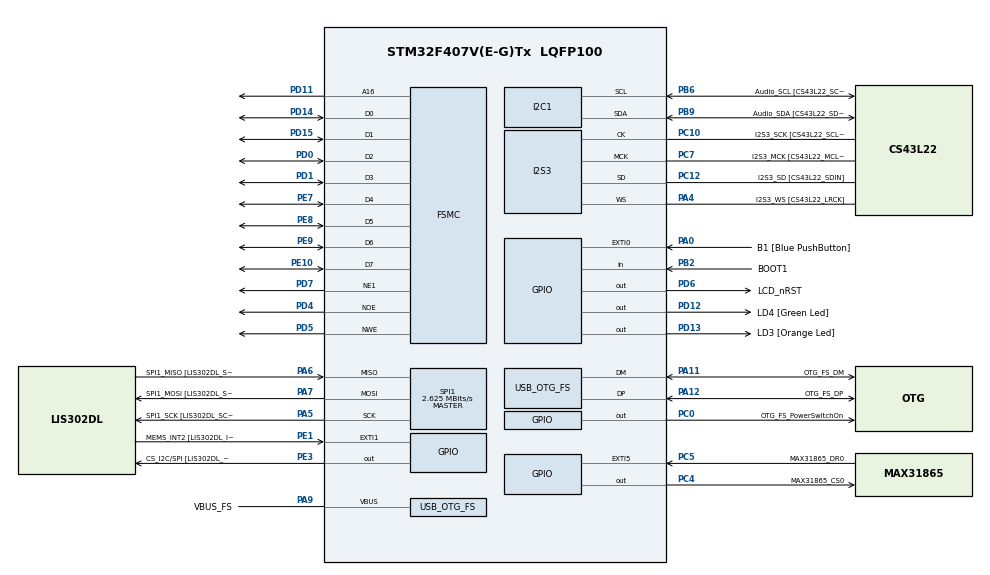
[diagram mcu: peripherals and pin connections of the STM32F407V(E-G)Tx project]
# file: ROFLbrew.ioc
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FSMC.BusTurnAroundDuration1=0
FSMC.DataSetupTime1=13
I2S3.AudioFreq=I2S_AUDIOFREQ_96K
I2S3.AudioFreq-Half_Duplex_Master=I2S_AUDIOFREQ_96K
I2S3.ErrorAudioFreq=-2.34 %
I2S3.ErrorAudioFreq-Half_Duplex_Master=0.8 %
I2S3.RealAudioFreq=93.75 KHz
I2S3.RealAudioFreq-Half_Duplex_Master=96.774 KHz
Mcu.Family=STM32F4
Mcu.Name=STM32F407V(E-G)Tx
Mcu.Package=LQFP100
NVIC.EXTI9_5_IRQn=true\:0\:0\:false\:false\:true
NVIC.OTG_FS_IRQn=true\:0\:0\:false\:false\:true
NVIC.PriorityGroup=NVIC_PRIORITYGROUP_0
NVIC.TIM8_TRG_COM_TIM14_IRQn=true\:0\:0\:false\:false\:true
PA0-WKUP.GPIO_Label=B1 [Blue PushButton]
PA0-WKUP.GPIO_ModeDefaultEXTI=GPIO_MODE_EVT_RISING
PA0-WKUP.GPIO_PuPd=GPIO_NOPULL
PA0-WKUP.Signal=GPXTI0
PA10.GPIO_Label=OTG_FS_ID
PA10.GPIO_Mode=GPIO_MODE_AF_PP
PA10.GPIO_PuPd=GPIO_NOPULL
PA10.GPIO_Speed=GPIO_SPEED_FREQ_LOW
PA10.Signal=USB_OTG_FS_ID
PA11.GPIO_Label=OTG_FS_DM
PA11.GPIO_Mode=GPIO_MODE_AF_PP
PA11.GPIO_PuPd=GPIO_NOPULL
PA11.GPIO_Speed=GPIO_SPEED_FREQ_LOW
PA11.Mode=Host_Only
PA11.Signal=USB_OTG_FS_DM
PA12.GPIO_Label=OTG_FS_DP
PA12.GPIO_Mode=GPIO_MODE_AF_PP
PA12.GPIO_PuPd=GPIO_NOPULL
PA12.GPIO_Speed=GPIO_SPEED_FREQ_LOW
PA12.Mode=Host_Only
PA12.Signal=USB_OTG_FS_DP
PA13.GPIO_Label=SWDIO
PA13.Mode=Serial_Wire
PA13.Signal=SYS_JTMS-SWDIO
PA14.GPIO_Label=SWCLK
PA14.Mode=Serial_Wire
PA14.Signal=SYS_JTCK-SWCLK
PA4.GPIO_Label=I2S3_WS [CS43L22_LRCK]
PA4.GPIO_Mode=GPIO_MODE_AF_PP
PA4.GPIO_PuPd=GPIO_NOPULL
PA4.GPIO_Speed=GPIO_SPEED_FREQ_LOW
PA4.Mode=Half_Duplex_Master
PA4.Signal=I2S3_WS
PA5.GPIO_Label=SPI1_SCK [LIS302DL_SCL/SPC]
PA5.GPIO_Mode=GPIO_MODE_AF_PP
PA5.GPIO_PuPd=GPIO_NOPULL
PA5.GPIO_Speed=GPIO_SPEED_FREQ_LOW
PA5.Mode=Full_Duplex_Master
PA5.Signal=SPI1_SCK
PA6.GPIO_Label=SPI1_MISO [LIS302DL_SDO]
PA6.GPIO_Mode=GPIO_MODE_AF_PP
PA6.GPIO_PuPd=GPIO_NOPULL
PA6.GPIO_Speed=GPIO_SPEED_FREQ_LOW
PA6.Mode=Full_Duplex_Master
PA6.Signal=SPI1_MISO
PA7.GPIO_Label=SPI1_MOSI [LIS302DL_SDA/SDI/SDO]
PA7.GPIO_Mode=GPIO_MODE_AF_PP
PA7.GPIO_PuPd=GPIO_NOPULL
PA7.GPIO_Speed=GPIO_SPEED_FREQ_LOW
PA7.Mode=Full_Duplex_Master
PA7.Signal=SPI1_MOSI
PA9.GPIO_Label=VBUS_FS
PA9.GPIO_Mode=GPIO_MODE_INPUT
PA9.GPIO_PuPd=GPIO_NOPULL
PA9.Mode=Activate_VBUS
PA9.Signal=USB_OTG_FS_VBUS
PB10.GPIO_Label=CLK_IN [MP45DT02_CLK]
PB10.GPIO_Mode=GPIO_MODE_AF_PP
PB10.GPIO_PuPd=GPIO_NOPULL
PB10.GPIO_Speed=GPIO_SPEED_FREQ_LOW
PB10.Signal=I2S2_CK
PB2.GPIO_Label=BOOT1
PB2.GPIO_Mode=GPIO_MODE_INPUT
PB2.GPIO_PuPd=GPIO_NOPULL
PB2.Signal=GPIO_Input
PB3.GPIO_Label=SWO
PB3.Signal=SYS_JTDO-SWO
PB6.GPIO_Label=Audio_SCL [CS43L22_SCL]
PB6.GPIO_Mode=GPIO_MODE_AF_OD
PB6.GPIO_PuPd=GPIO_NOPULL
PB6.GPIO_Speed=GPIO_SPEED_FREQ_LOW
PB6.Mode=I2C
PB6.Signal=I2C1_SCL
PB9.GPIO_Label=Audio_SDA [CS43L22_SDA]
PB9.GPIO_Mode=GPIO_MODE_AF_OD
PB9.GPIO_PuPd=GPIO_NOPULL
PB9.GPIO_Speed=GPIO_SPEED_FREQ_LOW
PB9.Mode=I2C
PB9.Signal=I2C1_SDA
PC0.GPIO_Label=OTG_FS_PowerSwitchOn
PC0.GPIO_PuPd=GPIO_NOPULL
PC0.GPIO_Speed=GPIO_SPEED_FREQ_LOW
PC0.PinState=GPIO_PIN_SET
PC0.Signal=GPIO_Output
PC10.GPIO_Label=I2S3_SCK [CS43L22_SCLK]
PC10.GPIO_Mode=GPIO_MODE_AF_PP
PC10.GPIO_PuPd=GPIO_NOPULL
PC10.GPIO_Speed=GPIO_SPEED_FREQ_LOW
PC10.Mode=Half_Duplex_Master
PC10.Signal=I2S3_CK
PC12.GPIO_Label=I2S3_SD [CS43L22_SDIN]
PC12.GPIO_Mode=GPIO_MODE_AF_PP
PC12.GPIO_PuPd=GPIO_NOPULL
PC12.GPIO_Speed=GPIO_SPEED_FREQ_LOW
PC12.Mode=Half_Duplex_Master
PC12.Signal=I2S3_SD
PC14-OSC32_IN.GPIO_Label=PC14-OSC32_IN
PC14-OSC32_IN.Mode=LSE-External-Oscillator
PC14-OSC32_IN.Signal=RCC_OSC32_IN
PC15-OSC32_OUT.GPIO_Label=PC15-OSC32_OUT
PC15-OSC32_OUT.Mode=LSE-External-Oscillator
PC15-OSC32_OUT.Signal=RCC_OSC32_OUT
PC3.GPIO_Label=PDM_OUT [MP45DT02_DOUT]
PC3.GPIO_Mode=GPIO_MODE_AF_PP
PC3.GPIO_PuPd=GPIO_NOPULL
PC3.GPIO_Speed=GPIO_SPEED_FREQ_LOW
PC3.Signal=I2S2_SD
PC4.GPIO_Label=MAX31865_CS0
PC4.GPIO_Speed=GPIO_SPEED_FREQ_MEDIUM
PC4.PinState=GPIO_PIN_SET
PC4.Signal=GPIO_Output
PC5.GPIO_Label=MAX31865_DR0
PC5.GPIO_ModeDefaultEXTI=GPIO_MODE_IT_FALLING
PC5.GPIO_PuPd=GPIO_PULLUP
PC5.Signal=GPXTI5
PC7.GPIO_Label=I2S3_MCK [CS43L22_MCLK]
PC7.GPIO_Mode=GPIO_MODE_AF_PP
PC7.GPIO_PuPd=GPIO_NOPULL
PC7.GPIO_Speed=GPIO_SPEED_FREQ_LOW
PC7.Mode=Master_Clock_Activated
PC7.Signal=I2S3_MCK
PD0.Mode=8b-d1
PD0.Signal=FSMC_D2
PD1.Mode=8b-d1
PD1.Signal=FSMC_D3
PD11.Mode=A16_1
PD11.Signal=FSMC_A16
PD12.GPIO_Label=LD4 [Green Led]
PD12.GPIO_PuPd=GPIO_NOPULL
PD12.GPIO_Speed=GPIO_SPEED_FREQ_LOW
PD12.Signal=GPIO_Output
PD13.GPIO_Label=LD3 [Orange Led]
PD13.GPIO_PuPd=GPIO_NOPULL
PD13.GPIO_Speed=GPIO_SPEED_FREQ_LOW
PD13.Signal=GPIO_Output
PD14.Mode=8b-d1
PD14.Signal=FSMC_D0
PD15.Mode=8b-d1
PD15.Signal=FSMC_D1
PD4.Mode=Lcd1
PD4.Signal=FSMC_NOE
PD5.Mode=Lcd1
PD5.Signal=FSMC_NWE
PD6.GPIO_Label=LCD_nRST
PD6.GPIO_ModeDefaultOutputPP=GPIO_MODE_OUTPUT_OD
PD6.GPIO_PuPd=GPIO_PULLUP
PD6.PinState=GPIO_PIN_SET
PD6.Signal=GPIO_Output
PD7.Mode=NorPsramChipSelect1_1
PD7.Signal=FSMC_NE1
PE1.GPIO_Label=MEMS_INT2 [LIS302DL_INT2]
PE1.GPIO_ModeDefaultEXTI=GPIO_MODE_EVT_RISING
PE1.GPIO_PuPd=GPIO_NOPULL
PE1.Signal=GPXTI1
PE10.Mode=8b-d1
PE10.Signal=FSMC_D7
PE3.GPIO_Label=CS_I2C/SPI [LIS302DL_CS_I2C/SPI]
PE3.GPIO_PuPd=GPIO_NOPULL
PE3.GPIO_Speed=GPIO_SPEED_FREQ_LOW
PE3.PinState=GPIO_PIN_SET
PE3.Signal=GPIO_Output
PE7.Mode=8b-d1
PE7.Signal=FSMC_D4
PE8.Mode=8b-d1
PE8.Signal=FSMC_D5
PE9.Mode=8b-d1
PE9.Signal=FSMC_D6
PH0-OSC_IN.GPIO_Label=PH0-OSC_IN
PH0-OSC_IN.Mode=HSE-External-Oscillator
PH0-OSC_IN.Signal=RCC_OSC_IN
PH1-OSC_OUT.GPIO_Label=PH1-OSC_OUT
PH1-OSC_OUT.Mode=HSE-External-Oscillator
PH1-OSC_OUT.Signal=RCC_OSC_OUT
ProjectManager.HeapSize=0x200
ProjectManager.StackSize=0x400
ProjectManager.TargetToolchain=SW4STM32
RCC.48MHZClocksFreq_Value=48000000
RCC.AHBFreq_Value=168000000
RCC.APB1CLKDivider=RCC_HCLK_DIV4
RCC.APB1Freq_Value=42000000
RCC.APB1TimFreq_Value=84000000
RCC.APB2CLKDivider=RCC_HCLK_DIV2
RCC.APB2Freq_Value=84000000
RCC.APB2TimFreq_Value=168000000
RCC.CortexFreq_Value=168000000
RCC.HCLKFreq_Value=168000000
RCC.HSE_VALUE=8000000
RCC.HSI_VALUE=16000000
RCC.PLLM=8
RCC.PLLN=336
RCC.PLLQ=7
RCC.SYSCLKFreq_VALUE=168000000
RCC.SYSCLKSource=RCC_SYSCLKSOURCE_PLLCLK
RCC.VCOOutputFreq_Value=336000000
SPI1.BaudRatePrescaler=SPI_BAUDRATEPRESCALER_32
SPI1.BaudRatePrescaler-Full_Duplex_Master=SPI_BAUDRATEPRESCALER_2
SPI1.CLKPhase=SPI_PHASE_2EDGE
SPI1.CLKPolarity=SPI_POLARITY_HIGH
SPI1.CalculateBaudRate=2.625 MBits/s
SPI1.CalculateBaudRate-Full_Duplex_Master=42.0 MBits/s
SPI1.DataSize=SPI_DATASIZE_8BIT
SPI1.Mode=SPI_MODE_MASTER
SPI1.Mode-Full_Duplex_Master=SPI_MODE_MASTER
TIM14.Period=1000
TIM14.Prescaler=168
USB_HOST.BSP.number=1
USB_HOST.USBH_HandleTypeDef-CDC_FS=hUsbHostFS
USB_HOST.VirtualModeFS=Cdc
USB_HOST0.BSP.STBoard=false
USB_HOST0.BSP.i2caddr=0
USB_HOST0.BSP.i2creg=0
USB_HOST0.BSP.instance=PC0
USB_HOST0.BSP.ip=GPIO
USB_HOST0.BSP.mode=Output
USB_HOST0.BSP.name=Drive_VBUS_FS
USB_OTG_FS.phy_itface=HCD_PHY_EMBEDDED
VP_TIM14_VS_ClockSourceINT.Mode=Enable_Timer
VP_USB_HOST_VS_USB_HOST_CDC_FS.Mode=CDC_FS
board=STM32F4DISCOVERY

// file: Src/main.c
/**
 ******************************************************************************
 * File Name          : main.c
 * Description        : Main program body
 ******************************************************************************
 *
 * COPYRIGHT(c) 2016 STMicroelectronics
 *
 * Redistribution and use in source and binary forms, with or without modification,
 * are permitted provided that the following conditions are met:
 *   1. Redistributions of source code must retain the above copyright notice,
 *      this list of conditions and the following disclaimer.
 *   2. Redistributions in binary form must reproduce the above copyright notice,
 *      this list of conditions and the following disclaimer in the documentation
 *      and/or other materials provided with the distribution.
 *   3. Neither the name of STMicroelectronics nor the names of its contributors
 *      may be used to endorse or promote products derived from this software
 *      without specific prior written permission.
 *
 * THIS SOFTWARE IS PROVIDED BY THE COPYRIGHT HOLDERS AND CONTRIBUTORS "AS IS"
 * AND ANY EXPRESS OR IMPLIED WARRANTIES, INCLUDING, BUT NOT LIMITED TO, THE
 * IMPLIED WARRANTIES OF MERCHANTABILITY AND FITNESS FOR A PARTICULAR PURPOSE ARE
 * DISCLAIMED. IN NO EVENT SHALL THE COPYRIGHT HOLDER OR CONTRIBUTORS BE LIABLE
 * FOR ANY DIRECT, INDIRECT, INCIDENTAL, SPECIAL, EXEMPLARY, OR CONSEQUENTIAL
 * DAMAGES (INCLUDING, BUT NOT LIMITED TO, PROCUREMENT OF SUBSTITUTE GOODS OR
 * SERVICES; LOSS OF USE, DATA, OR PROFITS; OR BUSINESS INTERRUPTION) HOWEVER
 * CAUSED AND ON ANY THEORY OF LIABILITY, WHETHER IN CONTRACT, STRICT LIABILITY,
 * OR TORT (INCLUDING NEGLIGENCE OR OTHERWISE) ARISING IN ANY WAY OUT OF THE USE
 * OF THIS SOFTWARE, EVEN IF ADVISED OF THE POSSIBILITY OF SUCH DAMAGE.
 *
 ******************************************************************************
 */
#include "stm32f4xx_hal.h"
#include "i2c.h"
#include "i2s.h"
#include "spi.h"
#include "tim.h"
#include "usb_host.h"
#include "gpio.h"
#include "fsmc.h"

/* USER CODE BEGIN Includes */
#include "MAX31865.h"
/* USER CODE END Includes */

/* USER CODE BEGIN PV */
/* Private variables ---------------------------------------------------------*/

/* USER CODE END PV */

void SystemClock_Config(void);
void Error_Handler(void);
void MX_USB_HOST_Process(void);

/* USER CODE BEGIN PFP */
/* Private function prototypes -----------------------------------------------*/
#define LCD_REG8  (* ( (volatile uint8_t *) 0x60000000 ) ) /* RS = 0 */
#define LCD_RAM8  (* ( (volatile uint8_t *) 0x60010000 ) ) /* RS = 1 */

void LCD_Write_COM(char VL)
{
	LCD_REG8 = VL;
	/*asm ( "nop\n\t"
			"nop\n\t"
			"nop\n\t"
			"nop\n\t"
			"nop\n\t"
			"nop\n\t"
			"nop\n\t"
			"nop\n\t"
			"nop\n\t"
			"nop\n\t"
			"nop\n\t"
			"nop\n\t"
			"nop\n\t"
			"nop\n\t"
			"nop\n\t"
			"nop\n\t"
			"nop\n\t");*/
}

void LCD_Write_DATA(char VL)
{
	LCD_RAM8 = VL;
	/*asm ( "nop\n\t"
			"nop\n\t"
			"nop\n\t"
			"nop\n\t"
			"nop\n\t"
			"nop\n\t"
			"nop\n\t"
			"nop\n\t"
			"nop\n\t"
			"nop\n\t"
			"nop\n\t"
			"nop\n\t"
			"nop\n\t"
			"nop\n\t"
			"nop\n\t"
			"nop\n\t"
			"nop\n\t"
			"nop\n\t"
			"nop\n\t"
			"nop\n\t");*/
}

void setXY(uint16_t x1, uint16_t y1, uint16_t x2, uint16_t y2)
{
	uint16_t tmp;

	tmp = x1;
	x1 = y1;
	y1 = tmp;

	tmp = x2;
	x2 = y2;
	y2 = tmp;

	y1=319-y1;
	y2=319-y2;

	tmp = y1;
	y1 = y2;
	y2 = tmp;

	LCD_Write_COM(0x2a);
	LCD_Write_DATA(x1>>8);
	LCD_Write_DATA(x1);
	LCD_Write_DATA(x2>>8);
	LCD_Write_DATA(x2);
	LCD_Write_COM(0x2b);
	LCD_Write_DATA(y1>>8);
	LCD_Write_DATA(y1);
	LCD_Write_DATA(y2>>8);
	LCD_Write_DATA(y2);
	LCD_Write_COM(0x2c);

}
void clrXY()
{
	setXY( 0, 0, 319, 479 );
}

void fillScr1(uint16_t color)
{
	long i;
	char ch, cl;

	ch=(uint8_t)(color>>8);
	cl=(uint8_t)(color & 0xFF);

	clrXY();
	HAL_Delay(10);
	for (i=0; i<((319+1)*(479+1)); i++)
	{
		LCD_Write_DATA(ch);
		LCD_Write_DATA(cl);
	}
}

void fillScr(uint8_t r, uint8_t g, uint8_t b)
{
	uint16_t color = ((r&248)<<8 | (g&252)<<3 | (b&248)>>3);
	fillScr1(color);
}
/* USER CODE END PFP */

/* USER CODE BEGIN 0 */
volatile uint8_t lcd_rx[6];
/* USER CODE END 0 */

int main(void)
{

	/* MCU Configuration----------------------------------------------------------*/

	/* Reset of all peripherals, Initializes the Flash interface and the Systick. */
	HAL_Init();

	/* Configure the system clock */
	SystemClock_Config();

	/* Initialize all configured peripherals */
	MX_GPIO_Init();
	MX_I2C1_Init();
	MX_I2S3_Init();
	MX_SPI1_Init();
	MX_USB_HOST_Init();
	MX_TIM14_Init();
	MX_FSMC_Init();

	/* USER CODE BEGIN 2 */

	// Reset the LCD
	HAL_GPIO_WritePin(LCD_nRST_GPIO_Port, LCD_nRST_Pin, GPIO_PIN_RESET);
	HAL_Delay(50);
	HAL_GPIO_WritePin(LCD_nRST_GPIO_Port, LCD_nRST_Pin, GPIO_PIN_SET);
	HAL_Delay(50);

	HAL_TIM_Base_Start_IT( &htim14 );

	initSPIIdleClock();

	//setCfgReg_MAX31865( 0, (MAX_31865_CFG_VBIAS_ON | MAX_31865_CFG_CONVAUTO_ON | MAX_31865_CFG_FAULT_NONE | MAX_31865_CFG_50HZ_ON) );

	HAL_Delay(20);
	LCD_Write_COM(0x11);
	HAL_Delay(20);
	LCD_Write_COM(0xD0);
	LCD_Write_DATA(0x07);
	LCD_Write_DATA(0x42);
	LCD_Write_DATA(0x18);

	LCD_Write_COM(0xD1);
	LCD_Write_DATA(0x00);
	LCD_Write_DATA(0x07);
	LCD_Write_DATA(0x10);

	LCD_Write_COM(0xD2);
	LCD_Write_DATA(0x01);
	LCD_Write_DATA(0x02);

	LCD_Write_COM(0xC0);
	LCD_Write_DATA(0x10);
	LCD_Write_DATA(0x3B);
	LCD_Write_DATA(0x00);
	LCD_Write_DATA(0x00);
	LCD_Write_DATA(0x02);
	LCD_Write_DATA(0x11);

	LCD_Write_COM(0xC5);
	LCD_Write_DATA(0x03);

	LCD_Write_COM(0xC8);
	LCD_Write_DATA(0x00);
	LCD_Write_DATA(0x32);
	LCD_Write_DATA(0x36);
	LCD_Write_DATA(0x45);
	LCD_Write_DATA(0x06);
	LCD_Write_DATA(0x16);
	LCD_Write_DATA(0x37);
	LCD_Write_DATA(0x75);
	LCD_Write_DATA(0x77);
	LCD_Write_DATA(0x54);
	LCD_Write_DATA(0x0C);
	LCD_Write_DATA(0x00);

	LCD_Write_COM(0x36);
	LCD_Write_DATA(0x0A);

	LCD_Write_COM(0x3A);
	LCD_Write_DATA(0x55);

	LCD_Write_COM(0x2A);
	LCD_Write_DATA(0x00);
	LCD_Write_DATA(0x00);
	LCD_Write_DATA(0x01);
	LCD_Write_DATA(0x3F);

	LCD_Write_COM(0x2B);
	LCD_Write_DATA(0x00);
	LCD_Write_DATA(0x00);
	//LCD_Write_DATA(0x01);
	//LCD_Write_DATA(0xE0);
	LCD_Write_DATA(0x01);
	LCD_Write_DATA(0xDF);
	HAL_Delay(120);
	LCD_Write_COM(0x29);
	HAL_Delay(120);
	fillScr(255, 255, 255);
	HAL_Delay(120);
	fillScr(0, 0, 0);

	/* USER CODE END 2 */

	/* Infinite loop */
	while (1)
	{
		MX_USB_HOST_Process();

		/* USER CODE BEGIN 3 */
		//handleMAX31865Devices();
		LCD_REG8 = 0xBF;
		//LCD_REG8 = 0xAA;
		HAL_Delay(1);

		for ( uint32_t i = 0; i < 6; i++ )
		{
			lcd_rx[i] = LCD_RAM8;
		}

		//checkMAX31865WDG();
	}
	/* USER CODE END 3 */

}

/** System Clock Configuration
 */
void SystemClock_Config(void)
{

	RCC_OscInitTypeDef RCC_OscInitStruct;
	RCC_ClkInitTypeDef RCC_ClkInitStruct;
	RCC_PeriphCLKInitTypeDef PeriphClkInitStruct;

	__HAL_RCC_PWR_CLK_ENABLE();

	__HAL_PWR_VOLTAGESCALING_CONFIG(PWR_REGULATOR_VOLTAGE_SCALE1);

	RCC_OscInitStruct.OscillatorType = RCC_OSCILLATORTYPE_HSE;
	RCC_OscInitStruct.HSEState = RCC_HSE_ON;
	RCC_OscInitStruct.PLL.PLLState = RCC_PLL_ON;
	RCC_OscInitStruct.PLL.PLLSource = RCC_PLLSOURCE_HSE;
	RCC_OscInitStruct.PLL.PLLM = 8;
	RCC_OscInitStruct.PLL.PLLN = 336;
	RCC_OscInitStruct.PLL.PLLP = RCC_PLLP_DIV8; //RCC_PLLP_DIV2;
	RCC_OscInitStruct.PLL.PLLQ = 7;
	if (HAL_RCC_OscConfig(&RCC_OscInitStruct) != HAL_OK)
	{
		Error_Handler();
	}

	RCC_ClkInitStruct.ClockType = RCC_CLOCKTYPE_HCLK|RCC_CLOCKTYPE_SYSCLK
			|RCC_CLOCKTYPE_PCLK1|RCC_CLOCKTYPE_PCLK2;
	RCC_ClkInitStruct.SYSCLKSource = RCC_SYSCLKSOURCE_PLLCLK;
	RCC_ClkInitStruct.AHBCLKDivider = RCC_SYSCLK_DIV1;
	RCC_ClkInitStruct.APB1CLKDivider = RCC_HCLK_DIV4;
	RCC_ClkInitStruct.APB2CLKDivider = RCC_HCLK_DIV2;
	if (HAL_RCC_ClockConfig(&RCC_ClkInitStruct, FLASH_LATENCY_5) != HAL_OK)
	{
		Error_Handler();
	}

	PeriphClkInitStruct.PeriphClockSelection = RCC_PERIPHCLK_I2S;
	PeriphClkInitStruct.PLLI2S.PLLI2SN = 192;
	PeriphClkInitStruct.PLLI2S.PLLI2SR = 2;
	if (HAL_RCCEx_PeriphCLKConfig(&PeriphClkInitStruct) != HAL_OK)
	{
		Error_Handler();
	}

	HAL_SYSTICK_Config(HAL_RCC_GetHCLKFreq()/1000);

	HAL_SYSTICK_CLKSourceConfig(SYSTICK_CLKSOURCE_HCLK);

	/* SysTick_IRQn interrupt configuration */
	HAL_NVIC_SetPriority(SysTick_IRQn, 0, 0);
}

void Error_Handler(void)
{
	while(1)
	{
	}
}

/************************ (C) COPYRIGHT STMicroelectronics *****END OF FILE****/
